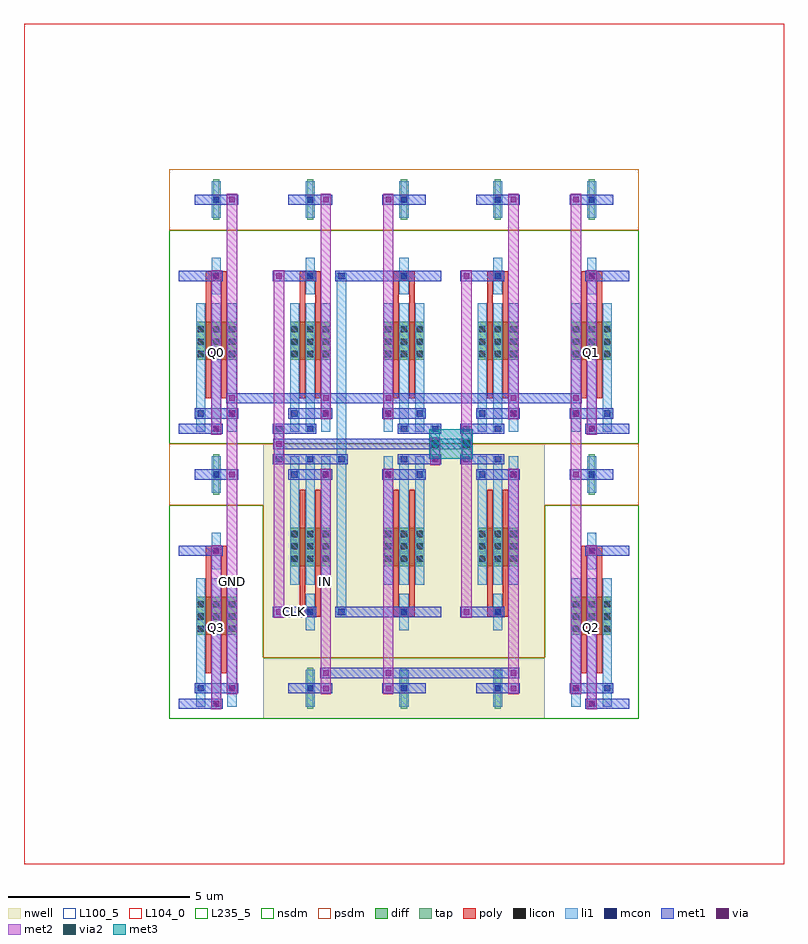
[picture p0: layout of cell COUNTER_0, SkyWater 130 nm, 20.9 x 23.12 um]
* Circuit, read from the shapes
.subckt COUNTER_0 CLK GND IN Q0 Q1 Q2 Q3
XM1 Q3 Q3 GND GND sky130_fd_pr__nfet_01v8 w=1.05 l=0.15 m=2
XM2 Q0 Q0 GND GND sky130_fd_pr__nfet_01v8 w=1.05 l=0.15 m=2
XM3 n1 CLK GND GND sky130_fd_pr__nfet_01v8 w=1.05 l=0.15 m=2
XM4 n2 n1 GND GND sky130_fd_pr__nfet_01v8 w=1.05 l=0.15 m=2
XM5 CLK n2 GND GND sky130_fd_pr__nfet_01v8 w=1.05 l=0.15 m=2
XM6 Q2 Q2 GND GND sky130_fd_pr__nfet_01v8 w=1.05 l=0.15 m=2
XM7 Q1 Q1 GND GND sky130_fd_pr__nfet_01v8 w=1.05 l=0.15 m=2
XM8 n1 CLK IN IN sky130_fd_pr__pfet_01v8 w=1.05 l=0.15 m=2
XM9 n2 n1 IN IN sky130_fd_pr__pfet_01v8 w=1.05 l=0.15 m=2
XM10 CLK n2 IN IN sky130_fd_pr__pfet_01v8 w=1.05 l=0.15 m=2
.ends

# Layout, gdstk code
from math import pi, radians
import gdstk
lib = gdstk.Library(unit=1e-6, precision=1e-09)
def R(c, l, rs):  # rectangles x0, y0, x1, y1
    for r in rs: c.add(gdstk.rectangle(r[:2], r[2:], *l))
def A(c, l, x, y, w, h, nx, ny, dx, dy):  # array of equal rectangles
    R(c, l, [(x+i*dx, y+j*dy, x+i*dx+w, y+j*dy+h) for i in range(nx) for j in range(ny)])
def P(c, l, *ps):  # polygons
    for p in ps: c.add(gdstk.Polygon(p, *l))
nwell = (64, 20)
diff = (65, 20)
tap = (65, 44)
poly = (66, 20)
licon = (66, 44)
li1 = (67, 20)
mcon = (67, 44)
met1 = (68, 20)
via = (68, 44)
met2 = (69, 20)
via2 = (69, 44)
met3 = (70, 20)
nsdm = (93, 44)
psdm = (94, 20)
L100_5 = (100, 5)
L104_0 = (104, 0)
L235_5 = (235, 5)

nmos_s_54487678_x1_y1_16 = lib.new_cell('NMOS_S_54487678_X1_Y1_1677829881_1677829882')
R(nmos_s_54487678_x1_y1_16, diff, [(0.735,2.31,1.845,3.36)])
R(nmos_s_54487678_x1_y1_16, tap, [(1.205,6.16,1.375,7.28)])
R(nmos_s_54487678_x1_y1_16, poly, [(1,1.26,1.15,4.62), (1.43,1.26,1.58,4.62), (1,4.485,1.58,4.755)])
A(nmos_s_54487678_x1_y1_16, licon, 0.775, 2.39, 0.17, 0.17, 3, 3, 0.43, 0.34)
R(nmos_s_54487678_x1_y1_16, licon, [(1.205,4.535,1.375,4.705), (1.205,6.635,1.375,6.805)])
A(nmos_s_54487678_x1_y1_16, li1, 0.735, 0.335, 0.25, 3.53, 3, 1, 0.43, 0)
R(nmos_s_54487678_x1_y1_16, li1, [(1.165,4.115,1.415,5.125), (1.165,6.215,1.415,7.225)])
R(nmos_s_54487678_x1_y1_16, mcon, [(1.205,0.335,1.375,0.505), (0.775,0.755,0.945,0.925), (1.635,0.755,1.805,0.925), (1.205,4.535,1.375,4.705), (1.205,6.635,1.375,6.805)])
R(nmos_s_54487678_x1_y1_16, met1, [(0.26,0.28,1.46,0.56), (0.69,0.7,1.89,0.98), (0.26,4.48,1.46,4.76), (0.69,6.58,1.89,6.86)])
R(nmos_s_54487678_x1_y1_16, via, [(1.645,0.765,1.795,0.915), (1.645,6.645,1.795,6.795)])
R(nmos_s_54487678_x1_y1_16, met2, [(1.58,0.68,1.86,6.88)])
R(nmos_s_54487678_x1_y1_16, nsdm, [(0,0,2.58,5.88)])
R(nmos_s_54487678_x1_y1_16, psdm, [(0,5.88,2.58,7.56)])
R(nmos_s_54487678_x1_y1_16, L100_5, [(0,0,2.58,7.56)])

pmos_s_87189516_x1_y1_16 = lib.new_cell('PMOS_S_87189516_X1_Y1_1677829882_1677829882')
R(pmos_s_87189516_x1_y1_16, nwell, [(0,0,2.58,7.56)])
R(pmos_s_87189516_x1_y1_16, diff, [(0.735,2.31,1.845,3.36)])
R(pmos_s_87189516_x1_y1_16, tap, [(1.205,6.16,1.375,7.28)])
R(pmos_s_87189516_x1_y1_16, poly, [(1,1.26,1.15,4.62), (1.43,1.26,1.58,4.62), (1,4.485,1.58,4.755)])
A(pmos_s_87189516_x1_y1_16, licon, 0.775, 2.39, 0.17, 0.17, 3, 3, 0.43, 0.34)
R(pmos_s_87189516_x1_y1_16, licon, [(1.205,4.535,1.375,4.705), (1.205,6.635,1.375,6.805)])
A(pmos_s_87189516_x1_y1_16, li1, 0.735, 0.335, 0.25, 3.53, 3, 1, 0.43, 0)
R(pmos_s_87189516_x1_y1_16, li1, [(1.165,4.115,1.415,5.125), (1.165,6.215,1.415,7.225)])
R(pmos_s_87189516_x1_y1_16, mcon, [(1.205,0.335,1.375,0.505), (0.775,0.755,0.945,0.925), (1.635,0.755,1.805,0.925), (1.205,4.535,1.375,4.705), (1.205,6.635,1.375,6.805)])
R(pmos_s_87189516_x1_y1_16, met1, [(0.26,0.28,1.46,0.56), (0.69,0.7,1.89,0.98), (0.26,4.48,1.46,4.76), (0.69,6.58,1.89,6.86)])
R(pmos_s_87189516_x1_y1_16, via, [(1.645,0.765,1.795,0.915), (1.645,6.645,1.795,6.795)])
R(pmos_s_87189516_x1_y1_16, met2, [(1.58,0.68,1.86,6.88)])
R(pmos_s_87189516_x1_y1_16, nsdm, [(0,5.88,2.58,7.56)])
R(pmos_s_87189516_x1_y1_16, psdm, [(0,0,2.58,5.88)])
R(pmos_s_87189516_x1_y1_16, L100_5, [(0,0,2.58,7.56)])

stage2_inv_91993238_0_0_ = lib.new_cell('STAGE2_INV_91993238_0_0_1677829882')
R(stage2_inv_91993238_0_0_, li1, [(2.885,2.855,3.135,3.025), (2.885,2.855,3.135,3.025), (2.885,2.94,3.135,7.98), (0.305,7.055,0.555,7.225), (0.305,7.055,0.555,7.225), (4.605,7.055,4.855,7.225), (4.605,7.055,4.855,7.225), (4.605,7.055,4.855,7.225), (4.605,7.055,4.855,7.225), (0.305,7.14,0.555,7.98), (4.605,7.14,4.855,7.98), (0.305,7.895,0.555,8.065), (0.305,7.895,0.555,8.065), (2.885,7.895,3.135,8.065), (2.885,7.895,3.135,8.065), (2.885,7.895,3.135,8.065), (2.885,7.895,3.135,8.065), (2.885,7.895,3.135,8.065), (2.885,7.895,3.135,8.065), (4.605,7.895,4.855,8.065), (4.605,7.895,4.855,8.065), (4.605,7.895,4.855,8.065), (4.605,7.895,4.855,8.065), (2.885,7.98,3.135,12.18), (2.885,12.095,3.135,12.265), (2.885,12.095,3.135,12.265), (2.885,12.095,3.135,12.265), (2.885,12.095,3.135,12.265), (2.885,12.095,3.135,12.265), (2.885,12.095,3.135,12.265)])
R(stage2_inv_91993238_0_0_, mcon, [(2.925,2.855,3.095,3.025), (2.925,2.855,3.095,3.025), (0.345,7.055,0.515,7.225), (0.345,7.055,0.515,7.225), (4.645,7.055,4.815,7.225), (4.645,7.055,4.815,7.225), (4.645,7.055,4.815,7.225), (4.645,7.055,4.815,7.225), (0.345,7.895,0.515,8.065), (0.345,7.895,0.515,8.065), (2.925,7.895,3.095,8.065), (2.925,7.895,3.095,8.065), (2.925,7.895,3.095,8.065), (2.925,7.895,3.095,8.065), (2.925,7.895,3.095,8.065), (2.925,7.895,3.095,8.065), (4.645,7.895,4.815,8.065), (4.645,7.895,4.815,8.065), (4.645,7.895,4.815,8.065), (4.645,7.895,4.815,8.065), (2.925,12.095,3.095,12.265), (2.925,12.095,3.095,12.265), (2.925,12.095,3.095,12.265), (2.925,12.095,3.095,12.265), (2.925,12.095,3.095,12.265), (2.925,12.095,3.095,12.265)])
R(stage2_inv_91993238_0_0_, met1, [(1.29,2.8,3.01,3.08), (2.84,2.8,3.18,3.08), (2.84,2.8,3.18,3.08), (4.57,2.8,4.89,3.08), (4.57,2.8,4.89,3.08), (1.56,6.16,1.88,6.44), (1.56,6.16,1.88,6.44), (1.72,6.16,3.44,6.44), (3.28,6.16,3.6,6.44), (3.28,6.16,3.6,6.44), (0.26,7,0.6,7.28), (0.26,7,0.6,7.28), (4.56,7,4.9,7.28), (4.56,7,4.9,7.28), (4.56,7,4.9,7.28), (4.56,7,4.9,7.28), (0.26,7.84,0.6,8.12), (0.26,7.84,0.6,8.12), (2.84,7.84,3.18,8.12), (2.84,7.84,3.18,8.12), (2.84,7.84,3.18,8.12), (2.84,7.84,3.18,8.12), (2.84,7.84,3.18,8.12), (2.84,7.84,3.18,8.12), (3.01,7.84,3.87,8.12), (4.56,7.84,4.9,8.12), (4.56,7.84,4.9,8.12), (4.56,7.84,4.9,8.12), (4.56,7.84,4.9,8.12), (1.29,12.04,3.01,12.32), (2.84,12.04,3.18,12.32), (2.84,12.04,3.18,12.32), (2.84,12.04,3.18,12.32), (2.84,12.04,3.18,12.32), (2.84,12.04,3.18,12.32), (2.84,12.04,3.18,12.32), (4.57,12.04,4.89,12.32), (4.57,12.04,4.89,12.32), (1.56,13.72,1.88,14), (1.56,13.72,1.88,14), (1.72,13.72,3.44,14), (3.28,13.72,3.6,14), (3.28,13.72,3.6,14)])
P(stage2_inv_91993238_0_0_, met1, [(0,0),(0,0),(0,0),(0,0)],
  [(0,0),(0,0),(0,0),(0,0)],
  [(0,0),(0,0),(0,0),(0,0)],
  [(0,0),(0,0),(0,0),(0,0)],
  [(0,0),(0,0),(0,0),(0,0)],
  [(0,0),(0,0),(0,0),(0,0)],
  [(0,0),(0,0),(0,0),(0,0)],
  [(0,0),(0,0),(0,0),(0,0)])
R(stage2_inv_91993238_0_0_, via, [(4.655,2.865,4.805,3.015), (4.655,2.865,4.805,3.015), (1.645,6.225,1.795,6.375), (1.645,6.225,1.795,6.375), (3.365,6.225,3.515,6.375), (3.365,6.225,3.515,6.375), (4.655,12.105,4.805,12.255), (4.655,12.105,4.805,12.255), (1.645,13.785,1.795,13.935), (1.645,13.785,1.795,13.935), (3.365,13.785,3.515,13.935), (3.365,13.785,3.515,13.935)])
R(stage2_inv_91993238_0_0_, met2, [(4.59,2.78,4.87,3.1), (4.59,2.78,4.87,3.1), (4.59,2.94,4.87,12.18), (1.58,6.14,1.86,6.46), (1.58,6.14,1.86,6.46), (3.3,6.14,3.58,6.46), (3.3,6.14,3.58,6.46), (4.59,12.02,4.87,12.34), (4.59,12.02,4.87,12.34), (1.58,13.7,1.86,14.02), (1.58,13.7,1.86,14.02), (3.3,13.7,3.58,14.02), (3.3,13.7,3.58,14.02)])
P(stage2_inv_91993238_0_0_, met2, [(0,0),(0,0),(0,0),(0,0)],
  [(0,0),(0,0),(0,0),(0,0)],
  [(0,0),(0,0),(0,0),(0,0)],
  [(0,0),(0,0),(0,0),(0,0)])
R(stage2_inv_91993238_0_0_, L235_5, [(0,0,5.16,15.12)])
stage2_inv_91993238_0_0_.add(gdstk.Reference(nmos_s_54487678_x1_y1_16, (5.16,7.56), rotation=pi))
stage2_inv_91993238_0_0_.add(gdstk.Reference(nmos_s_54487678_x1_y1_16, (0,7.56), x_reflection=True))
stage2_inv_91993238_0_0_.add(gdstk.Reference(pmos_s_87189516_x1_y1_16, (5.16,7.56), rotation=pi, x_reflection=True))
stage2_inv_91993238_0_0_.add(gdstk.Reference(pmos_s_87189516_x1_y1_16, (0,7.56)))

c_nmos_s_54487678_x1_y1_16 = lib.new_cell('NMOS_S_54487678_X1_Y1_1677829881_1677829881')
R(c_nmos_s_54487678_x1_y1_16, diff, [(0.735,2.31,1.845,3.36)])
R(c_nmos_s_54487678_x1_y1_16, tap, [(1.205,6.16,1.375,7.28)])
R(c_nmos_s_54487678_x1_y1_16, poly, [(1,1.26,1.15,4.62), (1.43,1.26,1.58,4.62), (1,4.485,1.58,4.755)])
A(c_nmos_s_54487678_x1_y1_16, licon, 0.775, 2.39, 0.17, 0.17, 3, 3, 0.43, 0.34)
R(c_nmos_s_54487678_x1_y1_16, licon, [(1.205,4.535,1.375,4.705), (1.205,6.635,1.375,6.805)])
A(c_nmos_s_54487678_x1_y1_16, li1, 0.735, 0.335, 0.25, 3.53, 3, 1, 0.43, 0)
R(c_nmos_s_54487678_x1_y1_16, li1, [(1.165,4.115,1.415,5.125), (1.165,6.215,1.415,7.225)])
R(c_nmos_s_54487678_x1_y1_16, mcon, [(1.205,0.335,1.375,0.505), (0.775,0.755,0.945,0.925), (1.635,0.755,1.805,0.925), (1.205,4.535,1.375,4.705), (1.205,6.635,1.375,6.805)])
R(c_nmos_s_54487678_x1_y1_16, met1, [(0.26,0.28,1.46,0.56), (0.69,0.7,1.89,0.98), (0.26,4.48,1.46,4.76), (0.69,6.58,1.89,6.86)])
R(c_nmos_s_54487678_x1_y1_16, via, [(1.645,0.765,1.795,0.915), (1.645,6.645,1.795,6.795)])
R(c_nmos_s_54487678_x1_y1_16, met2, [(1.58,0.68,1.86,6.88)])
R(c_nmos_s_54487678_x1_y1_16, nsdm, [(0,0,2.58,5.88)])
R(c_nmos_s_54487678_x1_y1_16, psdm, [(0,5.88,2.58,7.56)])
R(c_nmos_s_54487678_x1_y1_16, L100_5, [(0,0,2.58,7.56)])

c_pmos_s_87189516_x1_y1_16 = lib.new_cell('PMOS_S_87189516_X1_Y1_1677829882_1677829881')
R(c_pmos_s_87189516_x1_y1_16, nwell, [(0,0,2.58,7.56)])
R(c_pmos_s_87189516_x1_y1_16, diff, [(0.735,2.31,1.845,3.36)])
R(c_pmos_s_87189516_x1_y1_16, tap, [(1.205,6.16,1.375,7.28)])
R(c_pmos_s_87189516_x1_y1_16, poly, [(1,1.26,1.15,4.62), (1.43,1.26,1.58,4.62), (1,4.485,1.58,4.755)])
A(c_pmos_s_87189516_x1_y1_16, licon, 0.775, 2.39, 0.17, 0.17, 3, 3, 0.43, 0.34)
R(c_pmos_s_87189516_x1_y1_16, licon, [(1.205,4.535,1.375,4.705), (1.205,6.635,1.375,6.805)])
A(c_pmos_s_87189516_x1_y1_16, li1, 0.735, 0.335, 0.25, 3.53, 3, 1, 0.43, 0)
R(c_pmos_s_87189516_x1_y1_16, li1, [(1.165,4.115,1.415,5.125), (1.165,6.215,1.415,7.225)])
R(c_pmos_s_87189516_x1_y1_16, mcon, [(1.205,0.335,1.375,0.505), (0.775,0.755,0.945,0.925), (1.635,0.755,1.805,0.925), (1.205,4.535,1.375,4.705), (1.205,6.635,1.375,6.805)])
R(c_pmos_s_87189516_x1_y1_16, met1, [(0.26,0.28,1.46,0.56), (0.69,0.7,1.89,0.98), (0.26,4.48,1.46,4.76), (0.69,6.58,1.89,6.86)])
R(c_pmos_s_87189516_x1_y1_16, via, [(1.645,0.765,1.795,0.915), (1.645,6.645,1.795,6.795)])
R(c_pmos_s_87189516_x1_y1_16, met2, [(1.58,0.68,1.86,6.88)])
R(c_pmos_s_87189516_x1_y1_16, nsdm, [(0,5.88,2.58,7.56)])
R(c_pmos_s_87189516_x1_y1_16, psdm, [(0,0,2.58,5.88)])
R(c_pmos_s_87189516_x1_y1_16, L100_5, [(0,0,2.58,7.56)])

inv_51832211_0_0_1677829 = lib.new_cell('INV_51832211_0_0_1677829881')
R(inv_51832211_0_0_1677829, li1, [(2.025,7.055,2.275,7.225), (2.025,7.055,2.275,7.225), (2.025,7.14,2.275,7.98), (2.025,7.895,2.275,8.065), (2.025,7.895,2.275,8.065)])
R(inv_51832211_0_0_1677829, mcon, [(2.065,7.055,2.235,7.225), (2.065,7.055,2.235,7.225), (2.065,7.895,2.235,8.065), (2.065,7.895,2.235,8.065)])
R(inv_51832211_0_0_1677829, met1, [(1.99,2.8,2.31,3.08), (1.99,2.8,2.31,3.08), (1.98,7,2.32,7.28), (1.98,7,2.32,7.28), (1.98,7.84,2.32,8.12), (1.98,7.84,2.32,8.12), (1.99,12.04,2.31,12.32), (1.99,12.04,2.31,12.32)])
P(inv_51832211_0_0_1677829, met1, [(0,0),(0,0),(0,0),(0,0)],
  [(0,0),(0,0),(0,0),(0,0)],
  [(0,0),(0,0),(0,0),(0,0)],
  [(0,0),(0,0),(0,0),(0,0)])
R(inv_51832211_0_0_1677829, via, [(2.075,2.865,2.225,3.015), (2.075,2.865,2.225,3.015), (2.075,12.105,2.225,12.255), (2.075,12.105,2.225,12.255)])
R(inv_51832211_0_0_1677829, met2, [(2.01,2.78,2.29,3.1), (2.01,2.78,2.29,3.1), (2.01,2.94,2.29,12.18), (2.01,12.02,2.29,12.34), (2.01,12.02,2.29,12.34)])
P(inv_51832211_0_0_1677829, met2, [(0,0),(0,0),(0,0),(0,0)],
  [(0,0),(0,0),(0,0),(0,0)])
R(inv_51832211_0_0_1677829, L235_5, [(0,0,2.58,15.12)])
inv_51832211_0_0_1677829.add(gdstk.Reference(c_nmos_s_54487678_x1_y1_16, (2.58,7.56), rotation=pi))
inv_51832211_0_0_1677829.add(gdstk.Reference(c_pmos_s_87189516_x1_y1_16, (2.58,7.56), rotation=pi, x_reflection=True))

dcl_nmos_s_28285743_x1_y = lib.new_cell('DCL_NMOS_S_28285743_X1_Y1_1677829883')
R(dcl_nmos_s_28285743_x1_y, diff, [(0.735,2.31,1.845,3.36)])
R(dcl_nmos_s_28285743_x1_y, tap, [(1.205,6.16,1.375,7.28)])
R(dcl_nmos_s_28285743_x1_y, poly, [(1,1.26,1.15,4.62), (1.43,1.26,1.58,4.62), (1,4.485,1.58,4.755)])
A(dcl_nmos_s_28285743_x1_y, licon, 0.775, 2.39, 0.17, 0.17, 3, 3, 0.43, 0.34)
R(dcl_nmos_s_28285743_x1_y, licon, [(1.205,4.535,1.375,4.705), (1.205,6.635,1.375,6.805)])
A(dcl_nmos_s_28285743_x1_y, li1, 0.735, 0.335, 0.25, 3.53, 3, 1, 0.43, 0)
R(dcl_nmos_s_28285743_x1_y, li1, [(1.165,4.115,1.415,5.125), (1.165,6.215,1.415,7.225)])
R(dcl_nmos_s_28285743_x1_y, mcon, [(1.205,0.335,1.375,0.505), (0.775,0.755,0.945,0.925), (1.635,0.755,1.805,0.925), (1.205,4.535,1.375,4.705), (1.205,6.635,1.375,6.805)])
R(dcl_nmos_s_28285743_x1_y, met1, [(0.26,0.28,1.46,0.56), (0.69,0.7,1.89,0.98), (0.26,4.48,1.46,4.76), (0.69,6.58,1.89,6.86)])
R(dcl_nmos_s_28285743_x1_y, via, [(1.215,0.345,1.365,0.495), (1.645,0.765,1.795,0.915), (1.215,4.545,1.365,4.695), (1.645,6.645,1.795,6.795)])
R(dcl_nmos_s_28285743_x1_y, met2, [(1.15,0.26,1.43,4.78), (1.58,0.68,1.86,6.88)])
R(dcl_nmos_s_28285743_x1_y, nsdm, [(0,0,2.58,5.88)])
R(dcl_nmos_s_28285743_x1_y, psdm, [(0,5.88,2.58,7.56)])
R(dcl_nmos_s_28285743_x1_y, L100_5, [(0,0,2.58,7.56)])

counter_0 = lib.new_cell('COUNTER_0')
R(counter_0, li1, [(8.045,7.475,8.295,7.645), (8.045,7.475,8.295,7.645)])
P(counter_0, li1, [(0,0),(0,0),(0,0),(0,0)],
  [(0,0),(0,0),(0,0),(0,0)])
R(counter_0, mcon, [(8.085,7.475,8.255,7.645), (8.085,7.475,8.255,7.645)])
R(counter_0, met1, [(6.02,1.12,9.46,1.4), (9.3,1.12,9.62,1.4), (9.3,1.12,9.62,1.4), (7.15,7,7.47,7.28), (7.15,7,7.47,7.28), (2.85,7.42,3.17,7.7), (2.85,7.42,3.17,7.7), (3.01,7.42,8.17,7.7), (8,7.42,8.34,7.7), (8,7.42,8.34,7.7), (1.56,8.68,1.88,8.96), (1.56,8.68,1.88,8.96), (1.56,8.68,1.88,8.96), (1.56,8.68,1.88,8.96), (1.56,8.68,1.88,8.96), (1.56,8.68,1.88,8.96), (1.56,8.68,1.88,8.96), (1.56,8.68,1.88,8.96), (1.72,8.68,4.3,8.96), (6.02,8.68,9.46,8.96), (9.3,8.68,9.62,8.96), (9.3,8.68,9.62,8.96), (9.3,8.68,9.62,8.96), (9.3,8.68,9.62,8.96), (9.3,8.68,9.62,8.96), (9.3,8.68,9.62,8.96), (9.46,8.68,11.18,8.96), (11.02,8.68,11.34,8.96), (11.02,8.68,11.34,8.96), (11.02,8.68,11.34,8.96), (11.02,8.68,11.34,8.96)])
P(counter_0, met1, [(0,0),(0,0),(0,0),(0,0)],
  [(0,0),(0,0),(0,0),(0,0)],
  [(0,0),(0,0),(0,0),(0,0)],
  [(0,0),(0,0),(0,0),(0,0)],
  [(0,0),(0,0),(0,0),(0,0)],
  [(0,0),(0,0),(0,0),(0,0)],
  [(0,0),(0,0),(0,0),(0,0)],
  [(0,0),(0,0),(0,0),(0,0)],
  [(0,0),(0,0),(0,0),(0,0)],
  [(0,0),(0,0),(0,0),(0,0)],
  [(0,0),(0,0),(0,0),(0,0)],
  [(0,0),(0,0),(0,0),(0,0)],
  [(0,0),(0,0),(0,0),(0,0)],
  [(0,0),(0,0),(0,0),(0,0)],
  [(0,0),(0,0),(0,0),(0,0)],
  [(0,0),(0,0),(0,0),(0,0)],
  [(0,0),(0,0),(0,0),(0,0)],
  [(0,0),(0,0),(0,0),(0,0)],
  [(0,0),(0,0),(0,0),(0,0)])
R(counter_0, via, [(9.385,1.185,9.535,1.335), (9.385,1.185,9.535,1.335), (7.235,7.065,7.385,7.215), (7.235,7.065,7.385,7.215), (2.935,7.485,3.085,7.635), (2.935,7.485,3.085,7.635), (1.645,8.745,1.795,8.895), (1.645,8.745,1.795,8.895), (1.645,8.745,1.795,8.895), (1.645,8.745,1.795,8.895), (1.645,8.745,1.795,8.895), (1.645,8.745,1.795,8.895), (1.645,8.745,1.795,8.895), (1.645,8.745,1.795,8.895), (9.385,8.745,9.535,8.895), (9.385,8.745,9.535,8.895), (9.385,8.745,9.535,8.895), (9.385,8.745,9.535,8.895), (9.385,8.745,9.535,8.895), (9.385,8.745,9.535,8.895), (11.105,8.745,11.255,8.895), (11.105,8.745,11.255,8.895), (11.105,8.745,11.255,8.895), (11.105,8.745,11.255,8.895)])
R(counter_0, met2, [(9.32,1.1,9.6,1.42), (9.32,1.1,9.6,1.42), (1.58,6.72,1.86,8.4), (11.04,6.72,11.32,8.4), (7.17,6.98,7.45,7.3), (7.17,6.98,7.45,7.3), (7.17,7.14,7.45,7.56), (7.17,7.375,7.45,7.745), (7.17,7.375,7.45,7.745), (8.03,7.375,8.31,7.745), (8.03,7.375,8.31,7.745), (2.87,7.4,3.15,7.72), (2.87,7.4,3.15,7.72), (1.58,8.66,1.86,8.98), (1.58,8.66,1.86,8.98), (1.58,8.66,1.86,8.98), (1.58,8.66,1.86,8.98), (1.58,8.66,1.86,8.98), (1.58,8.66,1.86,8.98), (1.58,8.66,1.86,8.98), (1.58,8.66,1.86,8.98), (9.32,8.66,9.6,8.98), (9.32,8.66,9.6,8.98), (9.32,8.66,9.6,8.98), (9.32,8.66,9.6,8.98), (9.32,8.66,9.6,8.98), (9.32,8.66,9.6,8.98), (11.04,8.66,11.32,8.98), (11.04,8.66,11.32,8.98), (11.04,8.66,11.32,8.98), (11.04,8.66,11.32,8.98)])
P(counter_0, met2, [(0,0),(0,0),(0,0),(0,0)],
  [(0,0),(0,0),(0,0),(0,0)],
  [(0,0),(0,0),(0,0),(0,0)],
  [(0,0),(0,0),(0,0),(0,0)],
  [(0,0),(0,0),(0,0),(0,0)],
  [(0,0),(0,0),(0,0),(0,0)],
  [(0,0),(0,0),(0,0),(0,0)],
  [(0,0),(0,0),(0,0),(0,0)],
  [(0,0),(0,0),(0,0),(0,0)],
  [(0,0),(0,0),(0,0),(0,0)],
  [(0,0),(0,0),(0,0),(0,0)],
  [(0,0),(0,0),(0,0),(0,0)],
  [(0,0),(0,0),(0,0),(0,0)],
  [(0,0),(0,0),(0,0),(0,0)],
  [(0,0),(0,0),(0,0),(0,0)],
  [(0,0),(0,0),(0,0),(0,0)],
  [(0,0),(0,0),(0,0),(0,0)],
  [(0,0),(0,0),(0,0),(0,0)],
  [(0,0),(0,0),(0,0),(0,0)],
  [(0,0),(0,0),(0,0),(0,0)],
  [(0,0),(0,0),(0,0),(0,0)],
  [(0,0),(0,0),(0,0),(0,0)],
  [(0,0),(0,0),(0,0),(0,0)],
  [(0,0),(0,0),(0,0),(0,0)],
  [(0,0),(0,0),(0,0),(0,0)],
  [(0,0),(0,0),(0,0),(0,0)])
R(counter_0, via2, [(7.21,7.46,7.41,7.66), (7.21,7.46,7.41,7.66), (8.07,7.46,8.27,7.66), (8.07,7.46,8.27,7.66)])
R(counter_0, met3, [(7.145,7.16,7.475,7.96), (7.145,7.16,7.475,7.96), (7.31,7.16,8.17,7.96), (8.005,7.16,8.335,7.96), (8.005,7.16,8.335,7.96)])
R(counter_0, L104_0, [(-4,-4,16.9,19.12)])
R(counter_0, L235_5, [(0,0,12.9,15.12)])
counter_0.add(gdstk.Reference(stage2_inv_91993238_0_0_, (7.74,15.12), rotation=pi))
counter_0.add(gdstk.Reference(inv_51832211_0_0_1677829, (10.32,15.12), rotation=pi))
counter_0.add(gdstk.Reference(dcl_nmos_s_28285743_x1_y, (0,7.56)))
counter_0.add(gdstk.Reference(dcl_nmos_s_28285743_x1_y, (0,0)))
counter_0.add(gdstk.Reference(dcl_nmos_s_28285743_x1_y, (12.9,0), rotation=pi, x_reflection=True))
counter_0.add(gdstk.Reference(dcl_nmos_s_28285743_x1_y, (12.9,7.56), rotation=pi, x_reflection=True))
counter_0.add(gdstk.Label('GND', (1.72,3.78), layer=69, texttype=5))
counter_0.add(gdstk.Label('IN', (4.3,3.78), layer=69, texttype=5))
counter_0.add(gdstk.Label('CLK', (3.44,2.94), layer=68, texttype=5))
counter_0.add(gdstk.Label('Q0', (1.29,10.08), layer=69, texttype=5))
counter_0.add(gdstk.Label('Q3', (1.29,2.52), layer=69, texttype=5))
counter_0.add(gdstk.Label('Q2', (11.61,2.52), layer=69, texttype=5))
counter_0.add(gdstk.Label('Q1', (11.61,10.08), layer=69, texttype=5))

lib.write_gds('COUNTER_0.gds')
